VERSION 5.7 ;
  NOWIREEXTENSIONATPIN ON ;
  DIVIDERCHAR "/" ;
  BUSBITCHARS "[]" ;
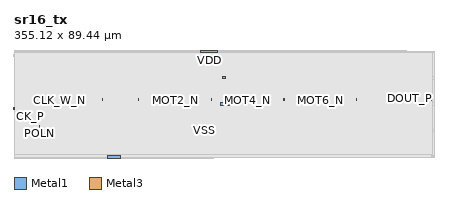
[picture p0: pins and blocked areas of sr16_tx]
MACRO sr16_tx
  CLASS BLOCK ;
  FOREIGN sr16_tx ;
  ORIGIN 0.000 0.000 ;
  SIZE 355.120 BY 89.440 ;
  PIN VDD
    DIRECTION INOUT ;
    USE POWER ;
    USE POWER ;
    PORT
      LAYER Metal1 ;
        RECT 78.900 -1.000 89.640 1.000 ;
    END
    PORT
      LAYER Metal1 ;
        RECT 174.900 43.720 181.800 45.720 ;
    END
    PORT
      LAYER Metal1 ;
        RECT 157.620 88.440 172.200 90.440 ;
    END
  END VDD
  PIN VSS
    DIRECTION INOUT ;
    USE GROUND ;
    USE GROUND ;
    PORT
      LAYER Metal1 ;
        RECT 156.530 21.360 165.830 23.360 ;
    END
    PORT
      LAYER Metal1 ;
        RECT 176.560 66.080 178.560 68.080 ;
    END
  END VSS
  PIN CK_N
    DIRECTION INPUT ;
    USE SIGNAL ;
    ANTENNAGATEAREA 2.160000 ;
    PORT
      LAYER Metal3 ;
        RECT -0.150 41.120 0.150 41.720 ;
    END
  END CK_N
  PIN CK_P
    DIRECTION INPUT ;
    USE SIGNAL ;
    ANTENNAGATEAREA 2.160000 ;
    PORT
      LAYER Metal3 ;
        RECT -0.150 40.020 0.150 40.620 ;
    END
  END CK_P
  PIN CLK_W_N
    DIRECTION INPUT ;
    USE SIGNAL ;
    ANTENNAGATEAREA 1.609200 ;
    PORT
      LAYER Metal3 ;
        RECT 38.250 47.870 38.550 48.170 ;
    END
  END CLK_W_N
  PIN CLK_W_P
    DIRECTION INPUT ;
    USE SIGNAL ;
    ANTENNAGATEAREA 1.609200 ;
    PORT
      LAYER Metal3 ;
        RECT 38.250 48.970 38.550 49.270 ;
    END
  END CLK_W_P
  PIN MOT0_N
    DIRECTION INPUT ;
    USE SIGNAL ;
    ANTENNAGATEAREA 0.889200 ;
    PORT
      LAYER Metal3 ;
        RECT 74.650 47.720 74.950 48.320 ;
    END
  END MOT0_N
  PIN MOT0_P
    DIRECTION INPUT ;
    USE SIGNAL ;
    ANTENNAGATEAREA 0.889200 ;
    PORT
      LAYER Metal3 ;
        RECT 74.650 48.820 74.950 49.420 ;
    END
  END MOT0_P
  PIN MOT1_N
    DIRECTION INPUT ;
    USE SIGNAL ;
    ANTENNAGATEAREA 0.889200 ;
    PORT
      LAYER Metal3 ;
        RECT 105.370 47.720 105.670 48.320 ;
    END
  END MOT1_N
  PIN MOT1_P
    DIRECTION INPUT ;
    USE SIGNAL ;
    ANTENNAGATEAREA 0.889200 ;
    PORT
      LAYER Metal3 ;
        RECT 105.370 48.820 105.670 49.420 ;
    END
  END MOT1_P
  PIN MOT2_N
    DIRECTION INPUT ;
    USE SIGNAL ;
    ANTENNAGATEAREA 0.889200 ;
    PORT
      LAYER Metal3 ;
        RECT 136.090 47.720 136.390 48.320 ;
    END
  END MOT2_N
  PIN MOT2_P
    DIRECTION INPUT ;
    USE SIGNAL ;
    ANTENNAGATEAREA 0.889200 ;
    PORT
      LAYER Metal3 ;
        RECT 136.090 48.820 136.390 49.420 ;
    END
  END MOT2_P
  PIN MOT3_N
    DIRECTION INPUT ;
    USE SIGNAL ;
    ANTENNAGATEAREA 0.889200 ;
    PORT
      LAYER Metal3 ;
        RECT 166.810 47.720 167.110 48.320 ;
    END
  END MOT3_N
  PIN MOT3_P
    DIRECTION INPUT ;
    USE SIGNAL ;
    ANTENNAGATEAREA 0.889200 ;
    PORT
      LAYER Metal3 ;
        RECT 166.810 48.820 167.110 49.420 ;
    END
  END MOT3_P
  PIN MOT4_N
    DIRECTION INPUT ;
    USE SIGNAL ;
    ANTENNAGATEAREA 0.889200 ;
    PORT
      LAYER Metal3 ;
        RECT 197.530 47.720 197.830 48.320 ;
    END
  END MOT4_N
  PIN MOT4_P
    DIRECTION INPUT ;
    USE SIGNAL ;
    ANTENNAGATEAREA 0.889200 ;
    PORT
      LAYER Metal3 ;
        RECT 197.530 48.820 197.830 49.420 ;
    END
  END MOT4_P
  PIN MOT5_N
    DIRECTION INPUT ;
    USE SIGNAL ;
    ANTENNAGATEAREA 0.889200 ;
    PORT
      LAYER Metal3 ;
        RECT 228.250 47.720 228.550 48.320 ;
    END
  END MOT5_N
  PIN MOT5_P
    DIRECTION INPUT ;
    USE SIGNAL ;
    ANTENNAGATEAREA 0.889200 ;
    PORT
      LAYER Metal3 ;
        RECT 228.250 48.820 228.550 49.420 ;
    END
  END MOT5_P
  PIN MOT6_N
    DIRECTION INPUT ;
    USE SIGNAL ;
    ANTENNAGATEAREA 0.889200 ;
    PORT
      LAYER Metal3 ;
        RECT 258.970 47.720 259.270 48.320 ;
    END
  END MOT6_N
  PIN MOT6_P
    DIRECTION INPUT ;
    USE SIGNAL ;
    ANTENNAGATEAREA 0.889200 ;
    PORT
      LAYER Metal3 ;
        RECT 258.970 48.820 259.270 49.420 ;
    END
  END MOT6_P
  PIN MOT7_N
    DIRECTION INPUT ;
    USE SIGNAL ;
    ANTENNAGATEAREA 0.889200 ;
    PORT
      LAYER Metal3 ;
        RECT 289.690 47.720 289.990 48.320 ;
    END
  END MOT7_N
  PIN MOT7_P
    DIRECTION INPUT ;
    USE SIGNAL ;
    ANTENNAGATEAREA 0.889200 ;
    PORT
      LAYER Metal3 ;
        RECT 289.690 48.820 289.990 49.420 ;
    END
  END MOT7_P
  PIN DOUT_N
    DIRECTION OUTPUT ;
    USE SIGNAL ;
    ANTENNADIFFAREA 3.091200 ;
    PORT
      LAYER Metal3 ;
        RECT 352.900 47.720 353.350 48.320 ;
    END
  END DOUT_N
  PIN DOUT_P
    DIRECTION OUTPUT ;
    USE SIGNAL ;
    ANTENNADIFFAREA 3.091200 ;
    PORT
      LAYER Metal3 ;
        RECT 353.050 48.820 353.350 49.420 ;
    END
  END DOUT_P
  PIN POLN
    DIRECTION INPUT ;
    USE SIGNAL ;
    ANTENNAGATEAREA 179.145203 ;
    PORT
      LAYER Metal3 ;
        RECT 21.450 25.070 21.880 26.390 ;
    END
  END POLN
  OBS
      LAYER GatPoly ;
        RECT 2.890 1.435 347.050 88.005 ;
      LAYER Metal1 ;
        RECT 0.000 89.295 157.620 90.440 ;
        RECT 172.200 89.440 332.080 90.440 ;
        RECT 0.000 88.260 157.440 89.295 ;
        RECT 172.200 88.845 355.120 89.440 ;
        RECT 172.380 88.260 355.120 88.845 ;
        RECT 0.000 68.260 355.120 88.260 ;
        RECT 0.000 65.900 176.380 68.260 ;
        RECT 178.740 65.900 355.120 68.260 ;
        RECT 0.000 45.900 355.120 65.900 ;
        RECT 0.000 43.540 174.720 45.900 ;
        RECT 181.980 43.540 355.120 45.900 ;
        RECT 0.000 23.540 355.120 43.540 ;
        RECT 0.000 21.180 156.350 23.540 ;
        RECT 166.010 21.180 355.120 23.540 ;
        RECT 0.000 1.180 355.120 21.180 ;
        RECT 0.000 0.145 78.720 1.180 ;
        RECT 89.820 0.595 355.120 1.180 ;
        RECT 0.000 -1.000 78.900 0.145 ;
        RECT 89.640 0.000 355.120 0.595 ;
        RECT 89.640 -1.000 168.880 0.000 ;
      LAYER Metal2 ;
        RECT 26.470 89.440 28.130 89.460 ;
        RECT 0.510 0.000 346.270 89.440 ;
        RECT 61.030 -0.020 62.690 0.000 ;
      LAYER Metal3 ;
        RECT 0.210 89.440 0.810 89.590 ;
        RECT 1.110 89.440 1.710 89.590 ;
        RECT 0.000 86.450 353.350 89.440 ;
        RECT 0.000 86.440 193.530 86.450 ;
        RECT -0.150 85.840 193.530 86.440 ;
        RECT 0.000 85.830 193.530 85.840 ;
        RECT 194.150 85.830 353.350 86.450 ;
        RECT 0.000 85.350 353.350 85.830 ;
        RECT 0.000 85.340 193.530 85.350 ;
        RECT -0.150 84.740 193.530 85.340 ;
        RECT 0.000 84.730 193.530 84.740 ;
        RECT 194.150 84.730 353.350 85.350 ;
        RECT 0.000 49.630 353.350 84.730 ;
        RECT 0.000 49.480 74.440 49.630 ;
        RECT 0.000 48.760 38.040 49.480 ;
        RECT 38.760 48.760 74.440 49.480 ;
        RECT 0.000 48.610 74.440 48.760 ;
        RECT 75.160 48.610 105.160 49.630 ;
        RECT 105.880 48.610 135.880 49.630 ;
        RECT 136.600 48.610 166.600 49.630 ;
        RECT 167.320 48.610 197.320 49.630 ;
        RECT 198.040 48.610 228.040 49.630 ;
        RECT 228.760 48.610 258.760 49.630 ;
        RECT 259.480 48.610 289.480 49.630 ;
        RECT 290.200 48.610 352.840 49.630 ;
        RECT 0.000 48.530 353.350 48.610 ;
        RECT 0.000 48.380 74.440 48.530 ;
        RECT 0.000 47.660 38.040 48.380 ;
        RECT 38.760 47.660 74.440 48.380 ;
        RECT 0.000 47.510 74.440 47.660 ;
        RECT 75.160 47.510 105.160 48.530 ;
        RECT 105.880 47.510 135.880 48.530 ;
        RECT 136.600 47.510 166.600 48.530 ;
        RECT 167.320 47.510 197.320 48.530 ;
        RECT 198.040 47.510 228.040 48.530 ;
        RECT 228.760 47.510 258.760 48.530 ;
        RECT 259.480 47.510 289.480 48.530 ;
        RECT 290.200 47.510 352.690 48.530 ;
        RECT 0.000 41.930 353.350 47.510 ;
        RECT 0.360 41.730 353.350 41.930 ;
        RECT 0.360 41.110 189.690 41.730 ;
        RECT 190.310 41.110 353.350 41.730 ;
        RECT 0.360 40.910 353.350 41.110 ;
        RECT 0.000 40.830 353.350 40.910 ;
        RECT 0.360 40.630 353.350 40.830 ;
        RECT 0.360 40.010 189.690 40.630 ;
        RECT 190.310 40.010 353.350 40.630 ;
        RECT 0.360 39.810 353.350 40.010 ;
        RECT 0.000 26.600 353.350 39.810 ;
        RECT 0.000 24.860 21.240 26.600 ;
        RECT 22.090 24.860 353.350 26.600 ;
        RECT 0.000 4.710 353.350 24.860 ;
        RECT 0.000 4.090 141.690 4.710 ;
        RECT 142.310 4.090 166.650 4.710 ;
        RECT 167.270 4.090 353.350 4.710 ;
        RECT 0.000 3.610 353.350 4.090 ;
        RECT 0.000 2.990 141.690 3.610 ;
        RECT 142.310 2.990 166.650 3.610 ;
        RECT 167.270 2.990 353.350 3.610 ;
        RECT 0.000 0.000 353.350 2.990 ;
        RECT 34.770 -0.150 35.370 0.000 ;
        RECT 35.670 -0.150 36.270 0.000 ;
      RECT 166.860 3.200 167.060 3.400 ;
      RECT 166.860 4.300 167.060 4.500 ;
      RECT 141.900 3.200 142.100 3.400 ;
      RECT 141.900 4.300 142.100 4.500 ;
      RECT 189.900 41.320 190.100 41.520 ;
      RECT 189.900 40.220 190.100 40.420 ;
      RECT 193.740 86.040 193.940 86.240 ;
      RECT 193.740 84.940 193.940 85.140 ;
      LAYER Metal4 ;
        RECT 0.155 2.195 353.845 88.285 ;
      RECT 166.860 3.200 167.060 3.400 ;
      RECT 166.860 4.300 167.060 4.500 ;
      RECT 141.900 3.200 142.100 3.400 ;
      RECT 141.900 4.300 142.100 4.500 ;
      RECT 189.900 41.320 190.100 41.520 ;
      RECT 189.900 40.220 190.100 40.420 ;
      RECT 193.740 86.040 193.940 86.240 ;
      RECT 193.740 84.940 193.940 85.140 ;
      LAYER Metal5 ;
        RECT 0.155 2.195 353.845 88.285 ;
  END
END sr16_tx
END LIBRARY

